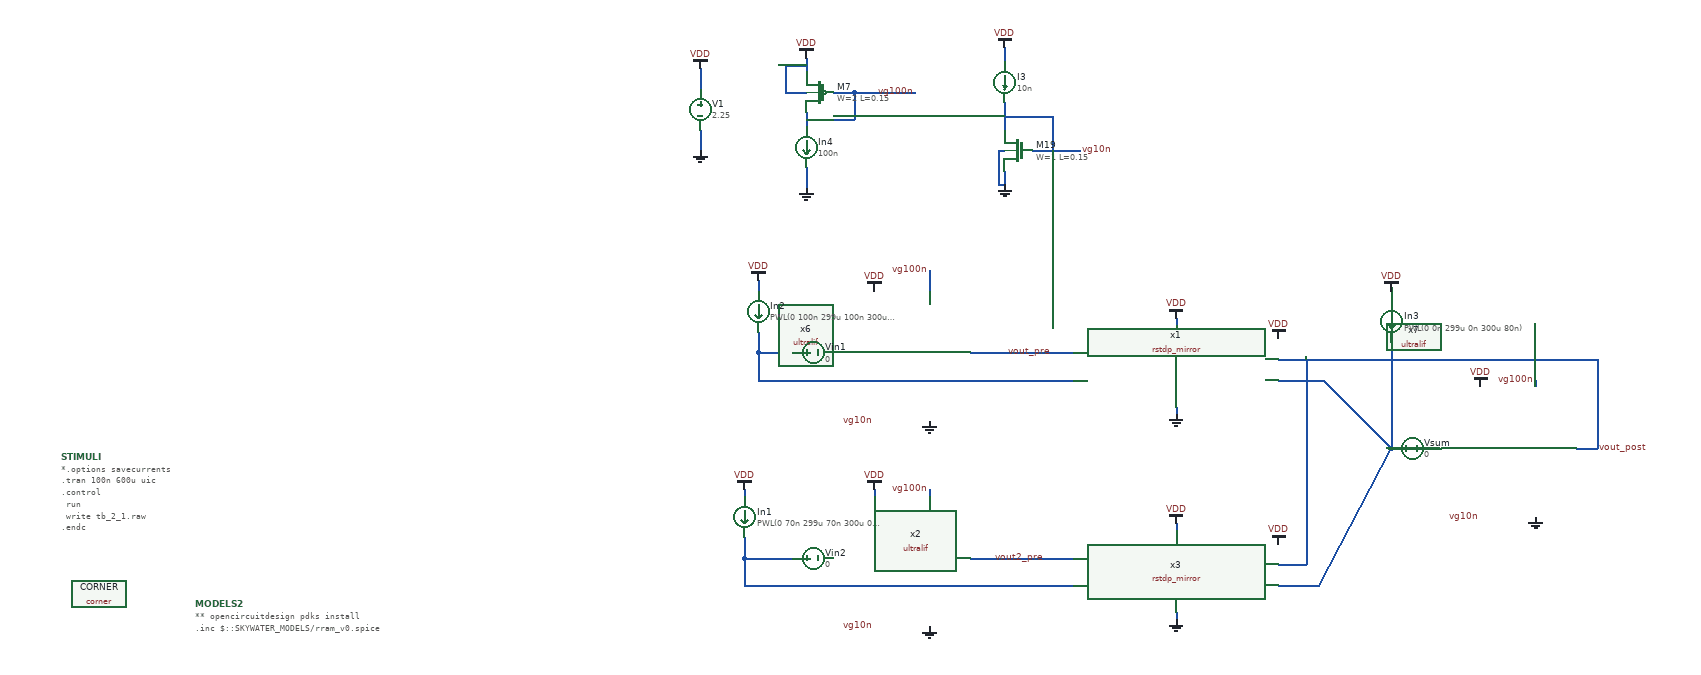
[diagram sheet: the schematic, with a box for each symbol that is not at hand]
v {xschem version=3.4.5 file_version=1.2
}
G {}
K {}
V {}
S {}
E {}
B 2 620 -780 1420 -380 {flags=graph
y1=1.5569444
y2=5.0569444
ypos1=0
ypos2=2
divy=5
subdivy=1
unity=1
x1=1e-09
x2=0.0006
divx=5
subdivx=1
xlabmag=1.0
ylabmag=1.0
node="\\"Fil1; 5 n.x1.x1.xr2.n1#ngap -\\"

\\"Fil2; 5 n.x3.x1.xr2.n1#ngap - \\""
color="6 8"
dataset=-1
unitx=1
logx=0
logy=0
}
B 2 1580 345 2380 745 {flags=graph
y1=-1.9478547
y2=2.0841453
ypos1=0
ypos2=2
divy=5
subdivy=1
unity=1
x1=1e-09
x2=0.0006
divx=5
subdivx=1
xlabmag=1.0
ylabmag=1.0


dataset=-1
unitx=1
logx=0
logy=0
color=4
node="\\"Vmem1; x1.x1.BE x1.x1.TE - \\""}
B 2 1580 -60 2380 340 {flags=graph
y1=-0.0056
y2=2.5
ypos1=0
ypos2=2
divy=5
subdivy=1
unity=1
x1=1e-09
x2=0.0006
divx=5
subdivx=1
xlabmag=1.0
ylabmag=1.0


dataset=-1
unitx=1
logx=0
logy=0
color=8
node=vout_post}
B 2 -1052.5 -805 -252.5 -405 {flags=graph
y1=-0.00026
y2=2.5
ypos1=0
ypos2=2
divy=5
subdivy=1
unity=1
x1=1e-09
x2=0.0006
divx=5
subdivx=1
xlabmag=1.0
ylabmag=1.0


dataset=-1
unitx=1
logx=0
logy=0
color=6
node=vout_pre}
B 2 -190 -890 610 -490 {flags=graph
y1=-2.4842771e-07
y2=9.0500577e-07
ypos1=0
ypos2=2
divy=5
subdivy=1
unity=1
x1=1e-09
x2=0.0006
divx=5
subdivx=1
xlabmag=1.0
ylabmag=1.0


dataset=-1
unitx=1
logx=0
logy=0
color=6
node=i(Vsum)}
B 2 -1145 -357.5 -345 42.5 {flags=graph
y1=-0.00027
y2=3.4
ypos1=0
ypos2=2
divy=5
subdivy=1
unity=1
x1=1e-09
x2=0.0006
divx=5
subdivx=1
xlabmag=1.0
ylabmag=1.0


dataset=-1
unitx=1
logx=0
logy=0
color=8
node=vout2_pre}
B 2 1562.5 -485 2362.5 -85 {flags=graph
y1=0.018
y2=1.8
ypos1=0
ypos2=2
divy=5
subdivy=1
unity=1
x1=1e-09
x2=0.0006
divx=5
subdivx=1
xlabmag=1.0
ylabmag=1.0


dataset=-1
unitx=1
logx=0
logy=0




color="4 7"
node="x7.vm
\\"Vth; 1.5\\""}
B 2 -242.5 520 557.5 920 {flags=graph
y1=-2.9558455e-07
y2=8.8406337e-07
ypos1=0
ypos2=2
divy=5
subdivy=1
unity=1
x1=1e-09
x2=0.0006
divx=5
subdivx=1
xlabmag=1.0
ylabmag=1.0


dataset=-1
unitx=1
logx=0
logy=0




color=6
node=i(vin1)}
B 2 607.5 505 1407.5 905 {flags=graph
y1=-2.3592474e-07
y2=7.0779367e-07
ypos1=0
ypos2=2
divy=5
subdivy=1
unity=1
x1=1e-09
x2=0.0006
divx=5
subdivx=1
xlabmag=1.0
ylabmag=1.0


dataset=-1
unitx=1
logx=0
logy=0




color=8
node=i(vin2)}
B 2 -1125 492.5 -325 892.5 {flags=graph
y1=0.018
y2=1.7
ypos1=0
ypos2=2
divy=5
subdivy=1
unity=1
x1=1e-09
x2=0.0006
divx=5
subdivx=1
xlabmag=1.0
ylabmag=1.0


dataset=-1
unitx=1
logx=0
logy=0

color="6 8"
node="x6.vm
x2.vm"}
N -145 -325 -145 -295 {
lab=GND}
N -145 -415 -145 -385 {
lab=VDD}
N 300 -365 300 -325 {
lab=vg10n}
N 300 -445 300 -425 {
lab=VDD}
N 300 -265 300 -245 {
lab=GND}
N 290 -295 300 -295 {
lab=GND}
N 290 -295 290 -245 {
lab=GND}
N 290 -245 300 -245 {
lab=GND}
N 340 -295 410 -295 {
lab=vg10n}
N 300 -345 370 -345 {
lab=vg10n}
N 370 -345 370 -295 {
lab=vg10n}
N 550 -50 550 -40 {
lab=VDD}
N 340 0 400 0 {
lab=vout_pre}
N 550 80 550 90 {
lab=GND}
N -60 -30 -60 0 {
lab=#net1}
N -80 270 -80 300 {
lab=#net2}
N -80 300 -10 300 {
lab=#net2}
N 110 200 110 210 {
lab=VDD}
N 550 250 550 260 {
lab=VDD}
N 550 380 550 390 {
lab=GND}
N 340 300 400 300 {
lab=vout2_pre}
N 1135 140 1165 140 {
lab=vout_post}
N 1165 10 1165 140 {
lab=vout_post}
N 10 -430 10 -410 {
lab=VDD}
N -20 -380 10 -380 {
lab=VDD}
N -20 -420 -20 -380 {
lab=VDD}
N -20 -420 10 -420 {
lab=VDD}
N 50 -380 80 -380 {
lab=vg100n}
N 10 -350 10 -330 {
lab=vg100n}
N 10 -340 80 -340 {
lab=vg100n}
N 80 -380 80 -340 {
lab=vg100n}
N 80 -380 170 -380 {
lab=vg100n}
N 190 -120 190 -90 {
lab=vg100n}
N 190 200 190 210 {
lab=vg100n}
N 1075 40 1075 50 {
lab=vg100n}
N 700 10 820 10 {
lab=vout_post}
N 820 10 930 10 {
lab=vout_post}
N 700 340 760 340 {
lab=#net3}
N 360 40 400 40 {
lab=#net1}
N 350 340 400 340 {
lab=#net2}
N 865 110 865 140 {
lab=#net3}
N 250 300 340 300 {
lab=vout2_pre}
N 740 10 740 305 {
lab=vout_post}
N 700 310 740 310 {
lab=vout_post}
N 740 305 740 310 {
lab=vout_post}
N 250 0 340 0 {
lab=vout_pre}
N 10 -270 10 -240 {
lab=GND}
N 925 140 935 140 {
lab=#net4}
N 860 140 865 140 {
lab=#net3}
N 930 10 1165 10 {
lab=vout_post}
N -60 -105 -60 -90 {
lab=VDD}
N -80 200 -80 210 {
lab=VDD}
N 865 -15 865 110 {
lab=#net3}
N 865 -95 865 -80 {
lab=VDD}
N 865 -80 865 -75 {
lab=VDD}
N 340 340 350 340 {
lab=#net2}
N -80 340 340 340 {
lab=#net2}
N -80 300 -80 340 {
lab=#net2}
N -60 40 360 40 {
lab=#net1}
N -60 -0 -60 40 {
lab=#net1}
N 700 40 765 40 {
lab=#net3}
N -60 0 -10 -0 {
lab=#net1}
N 765 40 865 140 {
lab=#net3}
N 760 340 865 140 {
lab=#net3}
C {devices/vsource.sym} -145 -355 0 0 {name=V1 value=2.25 savecurrent=false}
C {devices/vdd.sym} -145 -415 0 0 {name=l1 lab=VDD}
C {devices/gnd.sym} -145 -295 0 0 {name=l2 lab=GND}
C {sky130_fd_pr/corner.sym} -1022.5 352.5 0 0 {name=CORNER only_toplevel=true corner=tt}
C {devices/code_shown.sym} -1077.5 152.5 0 0 {name=STIMULI 
only_toplevel=true
place=end
value="
*.options savecurrents
.tran 100n 600u uic
.control
	run
	write tb_2_1.raw
.endc
"}
C {devices/code.sym} -882.5 367.5 0 0 {name=MODELS2
only_toplevel=true
format="tcleval( @value )"
value="
** opencircuitdesign pdks install
.inc $::SKYWATER_MODELS/rram_v0.spice
"
spice_ignore=false}
C {/home/alex/Desktop/EDA/SNN_IPN/Neuron/ultralif/ultralif.sym} 150 0 0 0 {name=x6}
C {/home/alex/Desktop/EDA/SNN_IPN/Neuron/ultralif/ultralif.sym} 1035 140 0 0 {name=x7}
C {sky130_fd_pr/nfet_01v8.sym} 320 -295 0 1 {name=M19
L=0.15
W=1
nf=1 
mult=1
ad="'int((nf+1)/2) * W/nf * 0.29'" 
pd="'2*int((nf+1)/2) * (W/nf + 0.29)'"
as="'int((nf+2)/2) * W/nf * 0.29'" 
ps="'2*int((nf+2)/2) * (W/nf + 0.29)'"
nrd="'0.29 / W'" nrs="'0.29 / W'"
sa=0 sb=0 sd=0
model=nfet_01v8
spiceprefix=X
}
C {devices/isource.sym} 300 -395 0 0 {name=I3 value=10n}
C {devices/vdd.sym} 300 -445 0 0 {name=l30 lab=VDD}
C {devices/gnd.sym} 300 -245 0 0 {name=l31 lab=GND}
C {devices/vdd.sym} 110 -90 0 0 {name=l3 lab=VDD}
C {devices/gnd.sym} 190 100 0 0 {name=l4 lab=GND}
C {devices/gnd.sym} 1075 240 0 0 {name=l5 lab=GND}
C {devices/vdd.sym} 995 50 0 0 {name=l6 lab=VDD}
C {devices/vdd.sym} 550 -50 0 0 {name=l10 lab=VDD}
C {devices/gnd.sym} 550 90 0 0 {name=l11 lab=GND}
C {devices/lab_pin.sym} 370 0 1 0 {name=p1 sig_type=std_logic lab=vout_pre}
C {devices/lab_pin.sym} 1165 140 0 1 {name=p3 sig_type=std_logic lab=vout_post}
C {devices/launcher.sym} -577.5 242.5 0 0 {name=h5
descr="load waves" 
tclcommand="xschem raw_read $netlist_dir/tb_2_1.raw tran"
}
C {/home/alex/Desktop/EDA/SNN_IPN/Neuron/ultralif/ultralif.sym} 150 300 0 0 {name=x2}
C {devices/gnd.sym} 190 400 0 0 {name=l7 lab=GND}
C {devices/vdd.sym} 110 200 0 0 {name=l13 lab=VDD}
C {devices/vdd.sym} 550 250 0 0 {name=l14 lab=VDD}
C {devices/gnd.sym} 550 390 0 0 {name=l15 lab=GND}
C {devices/lab_pin.sym} 360 300 1 0 {name=p5 sig_type=std_logic lab=vout2_pre}
C {devices/vdd.sym} 700 -20 0 0 {name=l9 lab=VDD}
C {sky130_fd_pr/pfet_01v8.sym} 30 -380 0 1 {name=M7
L=0.15
W=2
nf=1
mult=1
ad="'int((nf+1)/2) * W/nf * 0.29'" 
pd="'2*int((nf+1)/2) * (W/nf + 0.29)'"
as="'int((nf+2)/2) * W/nf * 0.29'" 
ps="'2*int((nf+2)/2) * (W/nf + 0.29)'"
nrd="'0.29 / W'" nrs="'0.29 / W'"
sa=0 sb=0 sd=0
model=pfet_01v8
spiceprefix=X
}
C {devices/vdd.sym} 10 -430 0 0 {name=l8 lab=VDD}
C {devices/isource.sym} 10 -300 0 1 {name=In4 value=100n }
C {devices/lab_pin.sym} 170 -380 3 0 {name=p7 sig_type=std_logic lab=vg100n}
C {devices/lab_pin.sym} 190 -120 1 0 {name=p8 sig_type=std_logic lab=vg100n}
C {devices/lab_pin.sym} 190 200 1 0 {name=p9 sig_type=std_logic lab=vg100n}
C {devices/lab_pin.sym} 1075 40 1 0 {name=p11 sig_type=std_logic lab=vg100n}
C {/home/alex/Desktop/EDA/SNN_IPN/Synapse/rstdp_mirror.sym} 550 0 0 0 {name=x1}
C {/home/alex/Desktop/EDA/SNN_IPN/Synapse/rstdp_mirror.sym} 550 300 0 0 {name=x3}
C {devices/isource.sym} -60 -60 0 1 {name=In2 value="PWL(0 100n 299u 100n 300u 0n)"
spice_ignore=false}
C {devices/vsource.sym} 895 140 3 0 {name=Vsum value=0 }
C {devices/isource.sym} -80 240 0 1 {name=In1 value="PWL(0 70n 299u 70n 300u 0n)"
spice_ignore=false}
C {devices/isource.sym} 865 -45 0 1 {name=In3 value="PWL(0 0n 299u 0n 300u 80n)"
spice_ignore=false}
C {devices/lab_pin.sym} 410 -295 2 0 {name=p6 sig_type=std_logic lab=vg10n}
C {devices/lab_pin.sym} 110 400 3 0 {name=p10 sig_type=std_logic lab=vg10n}
C {devices/lab_pin.sym} 110 100 3 0 {name=p12 sig_type=std_logic lab=vg10n}
C {devices/lab_pin.sym} 995 240 3 0 {name=p13 sig_type=std_logic lab=vg10n}
C {devices/vdd.sym} 700 280 0 0 {name=l20 lab=VDD}
C {devices/gnd.sym} 10 -240 0 0 {name=l17 lab=GND}
C {devices/vdd.sym} -60 -105 0 0 {name=l18 lab=VDD}
C {devices/vdd.sym} -80 200 0 0 {name=l12 lab=VDD}
C {devices/vdd.sym} 865 -90 0 0 {name=l16 lab=VDD}
C {devices/vsource.sym} 20 0 3 0 {name=Vin1 value=0 }
C {devices/vsource.sym} 20 300 3 0 {name=Vin2 value=0 }
